# Small asymmetric-pin cells for local placement integration tests.
VERSION 5.8 ;
BUSBITCHARS "[]" ;
DIVIDERCHAR "/" ;
UNITS
  DATABASE MICRONS 1000 ;
END UNITS
MANUFACTURINGGRID 0.001 ;
LAYER metal1
  TYPE ROUTING ;
  DIRECTION HORIZONTAL ;
  PITCH 0.2 ;
  WIDTH 0.1 ;
  SPACING 0.1 ;
END metal1
SITE smt_site
  CLASS CORE ;
  SYMMETRY Y ;
  SIZE 1 BY 2 ;
END smt_site
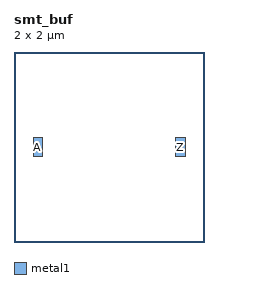
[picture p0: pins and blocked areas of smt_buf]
MACRO smt_buf
  CLASS CORE ;
  ORIGIN 0 0 ;
  SIZE 2 BY 2 ;
  SYMMETRY X Y ;
  SITE smt_site ;
  PIN A
    DIRECTION INPUT ;
    USE SIGNAL ;
    PORT
      LAYER metal1 ;
      RECT 0.2 0.9 0.3 1.1 ;
    END
  END A
  PIN Z
    DIRECTION OUTPUT ;
    USE SIGNAL ;
    PORT
      LAYER metal1 ;
      RECT 1.7 0.9 1.8 1.1 ;
    END
  END Z
END smt_buf
END LIBRARY
